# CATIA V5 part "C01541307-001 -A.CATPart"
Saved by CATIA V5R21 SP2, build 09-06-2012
Part number: C01541307-001
Revision: ---
Description: PROPRIETARY NOTICE (do not delete / modify)  ***************************************************************************************************  LA SOCIETE EN COMMANDITE  AIRBUS CANADA  ("AIRBUS CANADA")  PAR  L'INTERMEDIAIRE  DE  SES  DIVISIONS  ET/OU  FILIALES  CORPORATIVES,  FOURNIT  LES PRESENTES  INFORMATIONS  AU  GOUVERNEMENT  A  TITRE CONFIDENTIEL. CES  INFORMATIONS ONT UNE TENEUR CONFIDENTIELLE,  AVEC DROITS DE PROPRIETE,  ET NOUS LES CONSIDERONS  EXCLUS  DE   L'APPLICATION  DE  LA LOI SUR L'ACCES A L'INFORMATION  (CANADA),  LES  LOIS  SUR  L'ACCES  A  L'INFORMATION  EUROPEENNES,  LE FREEDOM OF INFORMATION ACT (ETATS-UNIS) ET D'AUTRES LOIS SEMBLABLES. ELLES  PEUVENT  AUSSI  CONSTITUER DES SECRETS INDUSTRIELS DE NOTRE SOCIETE OU DE TIERCES PARTIES. LA DIVULGATION  PUBLIQUE  DE CES  INFORMATIONS NUIRAIT A AIRBUS CANADA OU A DES TIERCES PARTIES.  CES INFORMATIONS PEUVENT EGALEMENT CONTENIR  DES DONNEES QUI SONT CONTROLEE PAR DES LOIS DE CONTROLE DES EXPORTATIONS DU CANADA, L’EUROPE OU LES  ETATS-  UNIS. TOUTE EXPORTATION OU REEXPORTATION DE DONNEES CONTROLEES SANS AUTORISATION EST STRICTEMENT INTERDITE.  TOUTE INTENTION DE LES DIVULGUER EN TOUT OU EN PARTIE DEVRA ETRE SIGNIFIEE A L'AVANCE ET PAR ECRIT AU VICE-  PRESIDENT, SERVICES JURIDIQUES ET CONFORMITE ET SECRETAIRE CORPORATIF D'AIRBUS CANADA.    AIRBUS CANADA LIMITED PARTNERSHIP  ("AIRBUS CANADA"),  BY ITS AFFILIATES AND/OR SUBSIDIARIES, PROVIDES THIS  INFORMATION TO THE GOVERNMENT IN CONFIDENCE. THIS IS PROPRIETARY CONFIDENTIAL INFORMATION WHICH WE CONSIDER  EXCLUDED  FROM  THE  APPLICATION OF THE ACCESS TO INFORMATION ACT (CANADA),  THE FREEDOM OF INFORMATION ACT  (U.S.A.),  THE ACCESS TO INFORMATION LAWS IN EUROPE, AND OTHER SIMILAR LEGISLATION. AND MAY ALSO CONSTITUTE  TRADE SECRETS OF OUR  COMPANY OR THIRD PARTIES.  PUBLIC  RELEASE  OF  THIS INFORMATION  WOULD BE HARMFUL TO  AIRBUS CANADA OR THIRD PARTIES.  THIS  INFORMATION  MAY  ALSO  CONTAIN DATA THAT IS CONTROLLED BY CANADIAN,  EUROPEAN, OR U.S.A. EXPORT CONTROL LAWS. ANY UNAUTHORIZED EXPORT OR RE-EXPORT OF ANY EXPORT CONTROLLED DATA  IS STRICTLY PROHIBITED  ANY INTENTION TO DISCLOSE SUCH INFORMATION,  OR  PART THEREOF,  MUST BE NOTIFIED IN  ADVANCE AND IN WRITING TO THE VICE PRESIDENT, LEGAL AND COMPLIANCE AND CORPORATE SECRETARY OF AIRBUS CANADA.        LES RENSEIGNEMENTS,  LES DONNEES  ET  DESSINS  TECHNIQUES  DIVULGUES  DANS  LES PRESENTES SONT LA PROPRIETE  EXCLUSIVE DE LA SOCIETE EN COMMANDITE AIRBUS CANADA ("AIRBUS CANADA") OU COMPORTENT DES DROITS DE PROPRIETE  APPARTENANT  A  AUTRUI ET NE PEUVENT ETRE DIVULGUES  A  QUICONQUE  NI  UTILISES PAR QUI QUE CE SOIT SANS LE  CONSENTEMENT  ECRIT  D’AIRBUS  CANADA.  LE DETENTEUR DES  PRESENTES  S'ENGAGE, DANS TOUTES CIRCONSTANCES, A  GARDER CONFIDENTIELS LES DONNEES ET DESSINS TECHNIQUES QU'ELLES CONTIENNENT.   CE QUI PRECEDE NE S'APPLIQUE  PAS  AUX PERSONNES  QUI  ONT DES DROITS DE PROPRIETE SUR CES RENSEIGNEMENTS,  DONNEES TECHNIQUES ET DESSINS  DANS LA MESURE OU CES DROITS EXISTENT.    THE INFORMATION,  TECHNICAL DATA  AND  DESIGNS DISCLOSED HEREIN ARE THE EXCLUSIVE PROPERTY OF AIRBUS CANADA  LIMITED PARTNERSHIP  ("AIRBUS CANADA")  OR  CONTAIN PROPRIETARY RIGHTS OF OTHERS  AND ARE NOT TO BE USED OR  DISCLOSED  TO  OTHERS WITHOUT THE WRITTEN CONSENT OF AIRBUS CANADA.  THE RECIPIENT OF THIS DOCUMENT, BY ITS  RETENTION  AND  USE  AGREES TO  HOLD  IN  CONFIDENCE  THE  TECHNICAL DATA AND DESIGNS CONTAINED HEREIN. THE  FOREGOING SHALL NOT APPLY TO PERSONS HAVING PROPRIETARY RIGHTS TO SUCH INFORMATION,  TECHNICAL DATA OR SUCH  DESIGNS TO THE EXTENT THAT SUCH RIGHTS EXIST.    Copyright 2020 Airbus Canada Limited Partnership. All Rights Reserved.  ***********************************
Property "Title": "SPACER, LINK UPR AXIS, PASS SVCE DR"
Property "Dataset Type": "DETAIL"
Property "Supplier Name And CAGE Code": "AIRBUS CANADA LIMITED PARTNERSHIP L0J48"
Property "Major Supplier Code": "LP"
Property "3D Only": "Y"
Property "Material Form": "BAR - ROUND"
Property "Finish Code": "S010"
Property "PCCN": "2"
Property "Organization": "DESIGN"
Property "Design Authority Program": "BD-500"
Property "Color Coded": "N/A"
Property "Thickness": 0
Property "Inside Diameter": 0
Property "Outside Diameter": 1.75
Property "Length": 0
Property "Width": 0
Property "Wall": 0
Property "Wire Gauge": "-"
Property "Alloy": "15-5PH"
Property "Final Condition": "H1025"
Property "Density": "N/A"
Property "Form": "N/A"
Property "Grade/Composition": "N/A"
Property "Material Class": "N/A"
Property "Mesh Cell Size": "N/A"
Property "Standard Spec Die": "N/A"
Property "Type": "N/A"
Property "Style": "N/A"
Property "MFG Process": "MACHINED"
Property "Material Specification Production": "AMS5659"
Property "Material Description Production": "CRES"
Property "Dimensions": "DIMENSIONS ARE IN INCHES"
Property "Roughness": "ALL MACHINED SURFACES 125 Ra MAX"
Property "Eng. Tolerances": "LINEAR .XX= +/-.03; .XXX= +/-.010; ANGULAR= +/-0.5 DEG"
Property "Tool Design Tolerances": "LINEAR .X= +/-.06; .XX= +/-.015; .XXX= +/-.005; .XXXX= +/-.001; ANGULAR= +/-0.5 DEG"
Property "Project": "BA"
Publications: "PartBody", "Extract_Datum_B", "Extract_Datum_A", "Line.2", "Point.3", "REFERENCE PLANE"
Material "CRES-PH-15-5-BAR": density 7833.41 kg/m3
Bounding box of the stored display mesh (mm): x -28.698 to 0, y -19.05 to 19.05, z -25.4 to 25.4
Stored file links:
  C:\Users\CQQZ006\Desktop\A220钢钛件\舱门\C01541307-001\C01541307-001 -A.CATPart
  I:\Standard\Materials\Textures\steel100.jpeg

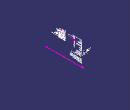
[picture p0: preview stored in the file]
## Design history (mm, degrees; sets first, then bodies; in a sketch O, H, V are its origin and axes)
Parameters
  deleted_LENGTH = 12.7 mm
AxisSystem1 "Absolute Axis System": origin (0, 0, 0), X (1, 0, 0), Y (0, 1, 0), Z (0, 0, 1)
Part_3D_Annotations1 "CATTPSSet"
Set1 "Pilot_Holes"
  Set2 "3/16"
    Point1: (-21.082, 0, 19.05 {= Sketch1.distance(L4 H)}), in AxisSystem1
    Line1: type PtDir, RefPoint Point1, Direction XY plane of AxisSystem1, Start 6.35, End -44.45
Set3 "References"
  Plane1 "REFERENCE PLANE": linked copy from another document
Set4 "Geometrical Set for 3D Annotations"
  Set5 "No Show Geometry"
    MultiExtract1 "Extract_Datum_B": ListOfMultiExtractConstraints (MultiExtractConstraint face of Shaft1 from Sketch1.L3; MultiExtractConstraint face of Shaft1 from Sketch1.L3)
    Extract1 "Extract_Datum_A": ExtractElem face of Shaft1 from Sketch1.L2
Body1 "PartBody" (main body)
  Sketch1 on zx-plane, origin (0, 0, 0), H (-1, 0, 0), V (0, 0, 1)
    line L1 (31.75, 19.05) -> (31.75, 16.6656)
    line L2 (31.75, 16.6656) -> (0, 16.6656)
    line L3 (0, 16.6656) -> (0, 19.05)
    line L4 (0, 19.05) -> (31.75, 19.05)
    distance L2 H = 16.6656
    distance L3 L1 = 31.75
    distance L4 H = 19.05
    horizontal: L2 H
    vertical: L1 V, L3 V
    coincidence: L3 V
  Shaft1: profile Sketch1, axis Sketch1.H, angle 360
  Body2
    Sketch2 on zx-plane, origin (0, 0, 0), H (-1, 0, 0), V (0, 0, 1)
      circle A1 centre (-8.89, 0) radius 15.875
      point P1 (-8.89, 0)
      radius A1 = 15.875
      distance V P1 = 8.89
      coincidence: P1 H
    Pad1: profile Sketch2, direction (0, 1, 0), length 31.75, mirrored extent
  Remove1: tool Body2
  Body3
    Sketch3 on xy-plane, origin (0, 0, 0), H (1, 0, 0), V (0, 1, 0)
      line L1 (-41.91, 28.4047) -> (-21.59, 28.4047)
      point P2 (-21.59, 28.4047)
      line L2 (-21.59, 28.4047) -> (-21.59, 13.9677)
      point P3 (-21.59, 13.9677)
      arc A1 centre (-28.702, 13.9677) radius 7.112 from (-21.59, 13.9677) to (-24.5185, 8.2163) cw
      arc A2 centre (-18.542, 0) radius 10.16 from (-24.5185, 8.2163) to (-24.5185, -8.2163) ccw
      point P6 (-18.542, 0)
      line L3 (-41.91, 28.4047) -> (-41.91, -28.4047)
      point P7 (-21.59, -13.9677)
      arc A3 centre (-28.702, -13.9677) radius 7.112 from (-21.59, -13.9677) to (-24.5185, -8.2163) ccw
      point P9 (-21.59, -28.4047)
      line L4 (-21.59, -28.4047) -> (-21.59, -13.9677)
      line L5 (-41.91, -28.4047) -> (-21.59, -28.4047)
      reference projected point E1 (-21.082, 0) from Line1
      radius A1 = 7.112
      radius A2 = 10.16
      distance L2 V = 21.59
      distance L1 H = 28.4047
      distance L3 L2 = 20.32
      distance A2 E1 = 7.62
      horizontal: L1 H
      vertical: L2 V, L3 V
      tangency: A1 L2, A2 A1, A2 A3
      symmetry: P3 P7 H, A1 A3 H, P2 P9 H, L2 L4 H, L1 L5 H
      coincidence: P6 H
    Pad2: profile Sketch3, direction (0, 0, 1), length 31.75, mirrored extent
  Remove2: tool Body3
